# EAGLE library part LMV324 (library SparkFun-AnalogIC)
Jellybean quad op-amp

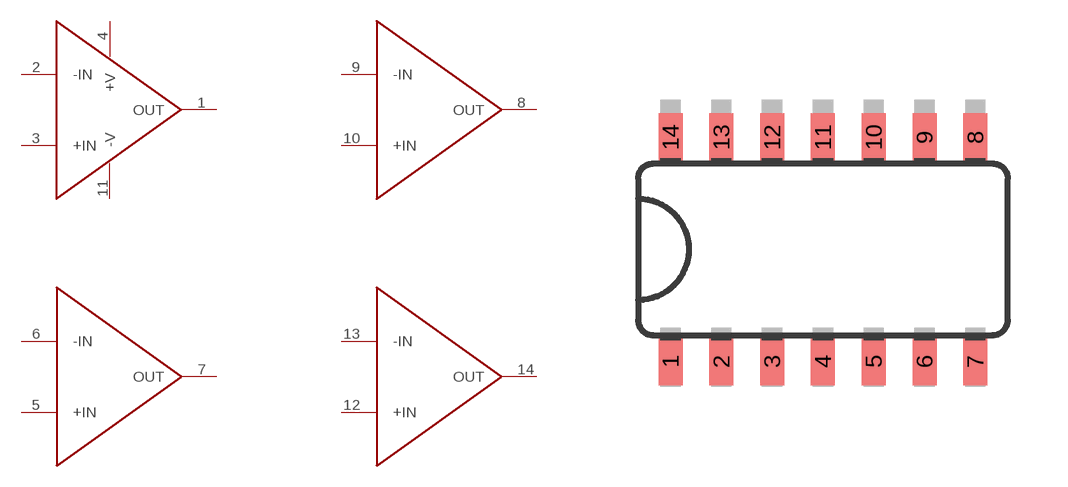
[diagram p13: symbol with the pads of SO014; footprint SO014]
Designator prefix -; gates G$1=LMV324 G$2=LMV324_2 G$3=LMV324_2 G$4=LMV324_2

## LMV324  [SO014]
1  G$1:OUT  out
2  G$1:-IN  in
3  G$1:+IN  in
4  G$1:+V  pwr
5  G$2:+IN  pwr
6  G$2:-IN  pwr
7  G$2:OUT  pwr
8  G$3:OUT  pwr
9  G$3:-IN  pwr
10  G$3:+IN  pwr
11  G$1:-V  pwr
12  G$4:+IN  pwr
13  G$4:-IN  pwr
14  G$4:OUT  pwr

## Footprint SO014 (pad centres in mm)
smd 0.6 x 1.2: 1 -3.175,-2.8; 2 -1.905,-2.8; 3 -0.635,-2.8; 4 0.635,-2.8; 5 1.905,-2.8; 6 3.175,-2.8; 7 4.445,-2.8; 8 4.445,2.8; 9 3.175,2.8; 10 1.905,2.8; 11 0.635,2.8; 12 -0.635,2.8; 13 -1.905,2.8; 14 -3.175,2.8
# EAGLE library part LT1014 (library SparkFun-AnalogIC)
Precision quad op-amp. I/O range includes negative rail.

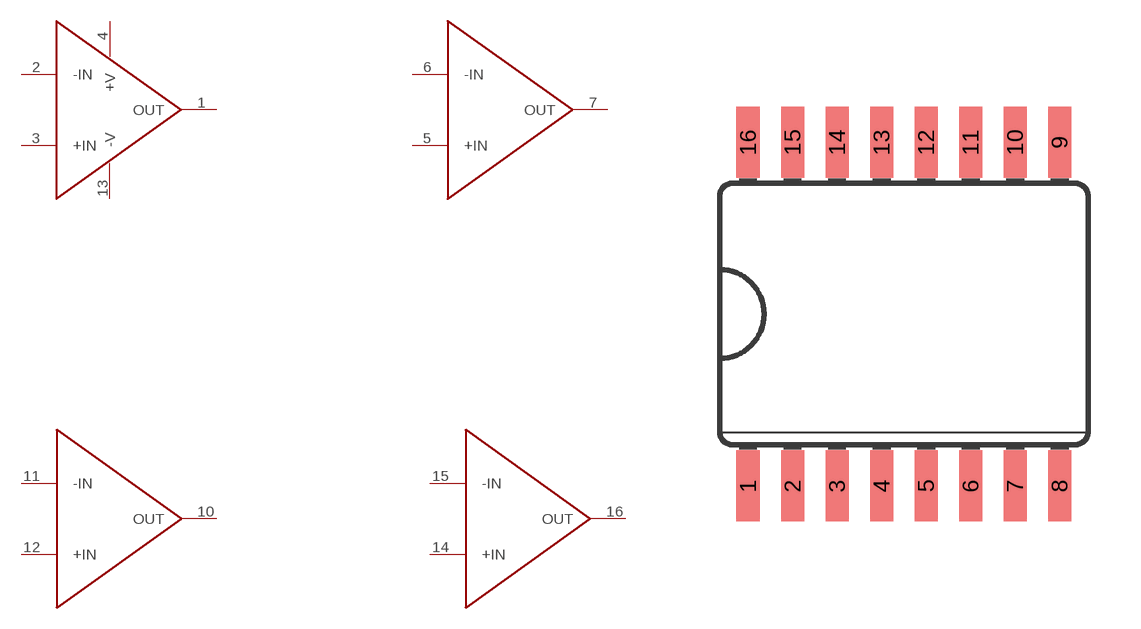
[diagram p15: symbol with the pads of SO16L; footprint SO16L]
Designator prefix -; gates G$1=LT1014 G$2=LT1014_2 G$3=LT1014_2 G$4=LT1014_2

## LT1014  [SO16L]
1  G$1:OUT  out
2  G$1:-IN  in
3  G$1:+IN  in
4  G$1:+V  pwr
5  G$2:+IN  pwr
6  G$2:-IN  pwr
7  G$2:OUT  pwr
10  G$3:OUT  pwr
11  G$3:-IN  pwr
12  G$3:+IN  pwr
13  G$1:-V  pwr
14  G$4:+IN  pwr
15  G$4:-IN  pwr
16  G$4:OUT  pwr

## Footprint SO16L (pad centres in mm)
Small Outline Package .300 SIOC Source: http://www.maxim-ic.com/cgi-bin/packages?pkg=16%2FSOIC%2E300&Type=Max
smd 0.66 x 2.032: 1 -4.445,-4.902; 2 -3.175,-4.902; 3 -1.905,-4.902; 4 -0.635,-4.902; 5 0.635,-4.902; 6 1.905,-4.902; 7 3.175,-4.902; 8 4.445,-4.902; 9 4.445,4.902; 10 3.175,4.902; 11 1.905,4.902; 12 0.635,4.902; 13 -0.635,4.902; 14 -1.905,4.902; 15 -3.175,4.902; 16 -4.445,4.902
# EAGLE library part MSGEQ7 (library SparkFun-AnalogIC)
7-band graphic equalizer

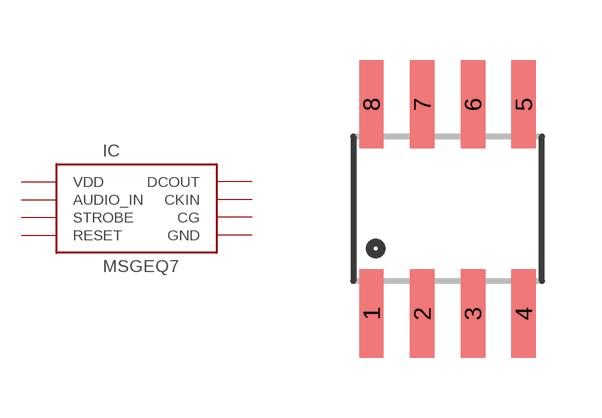
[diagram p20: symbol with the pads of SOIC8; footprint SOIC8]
Designator prefix IC

## MSGEQ7SOIC  [SOIC8]
1  VDD  in
2  GND
3  DCOUT
4  STROBE  in
5  AUDIO_IN  in
6  CG
7  RESET  in
8  CKIN

## Footprint SOIC8 (pad centres in mm)
smd 0.61 x 2.21: 1 -1.905,-2.616; 2 -0.635,-2.616; 3 0.635,-2.616; 4 1.905,-2.616; 5 1.905,2.616; 6 0.635,2.616; 7 -0.635,2.616; 8 -1.905,2.616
